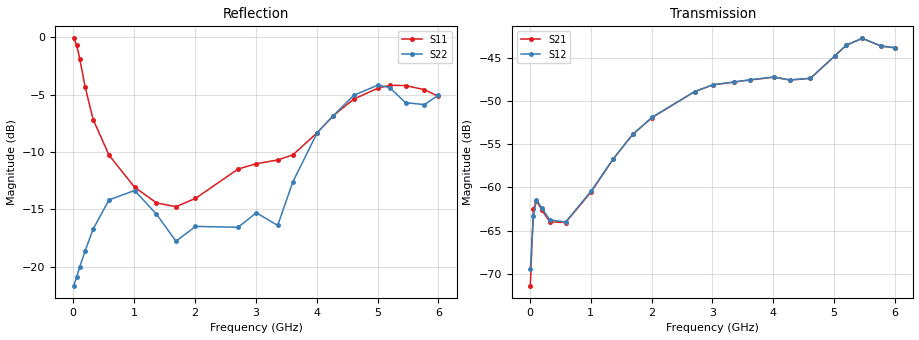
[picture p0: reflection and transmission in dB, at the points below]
!Agilent Technologies,N5230A,MY45001650,A.07.50.48
!Agilent N5230A: A.07.50.48
!Date: Saturday, July 08, 2017 15:49:07
!Correction: S11(Full 2 Port(1,2))
!S21(Full 2 Port(1,2))
!S12(Full 2 Port(1,2))
!S22(Full 2 Port(1,2))
!S2P File: Measurements: S11, S21, S12, S22:
# Hz S  dB  R 50
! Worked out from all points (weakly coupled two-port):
!   600 points, 10 MHz to 6 GHz, reference 50 ohm
!   highest |S21| = -42.73 dB at 5.46 GHz (marker M1); lowest = -71.4 dB at 10 MHz (marker M2)
!   lowest |S11| = -14.8 dB at 1.69 GHz (marker M3), VSWR 1.45, Z = 34.6 + j1.17 ohm
!   |S11| at or under -10 dB: 552.8 MHz to 3.663 GHz (3.11 GHz wide, 148 % of centre)
!   |S22| runs from -21.6 to -4.1 dB; largest |S21 - S12| = 0.00052
!   S11 on the Smith chart (normalised r, x): 10 MHz: 3, -20; 110 MHz: 0.52, -1.89; 330 MHz: 0.55, -0.56; 2.71 GHz: 0.59, +0.09; 4.27 GHz: 1.39, +1.14; 6 GHz: 2.58, -1.43
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1e7  -0.11 -5.7  -71.39 -163.1  -69.43 78.4  -21.65 -6.3
6e7  -0.70 -31.6  -62.51 26.6  -63.35 24.8  -20.89 -20.2
1.1e8  -1.91 -53.1  -61.55 -7.9  -61.43 -8.8  -20.00 -35.1
2e8  -4.38 -81.2  -62.64 -41.7  -62.42 -42.0  -18.59 -57.9
3.3e8  -7.18 -109.0  -63.99 -69.0  -63.77 -69.9  -16.71 -82.8
5.9e8  -10.28 -143.8  -64.07 -114.5  -64.01 -114.3  -14.18 -116.4
1.01e9  -13.07 -172.4  -60.51 -176.9  -60.41 -177.2  -13.36 -153.3
1.37e9  -14.44 174.1  -56.72 141.1  -56.70 141.3  -15.42 174.8
1.69e9  -14.77 174.8  -53.86 107.8  -53.87 107.8  -17.78 168.9
2.01e9  -14.05 177.0  -51.91 77.3  -51.86 77.2  -16.49 159.7
2.71e9  -11.49 164.5  -48.89 20.6  -48.89 20.5  -16.56 137.0
3.01e9  -11.03 149.3  -48.12 -4.4  -48.11 -4.4  -15.30 132.1
3.36e9  -10.70 124.6  -47.79 -31.9  -47.78 -31.9  -16.40 149.6
3.61e9  -10.26 102.1  -47.56 -49.9  -47.53 -49.8  -12.60 168.7
4.01e9  -8.32 64.2  -47.23 -80.3  -47.21 -80.0  -8.32 157.7
4.27e9  -6.86 45.6  -47.55 -99.6  -47.55 -99.6  -6.87 150.4
4.61e9  -5.40 27.7  -47.37 -116.6  -47.35 -116.6  -5.07 133.8
5.01e9  -4.44 13.0  -44.77 -145.6  -44.75 -145.4  -4.17 104.2
5.2e9  -4.20 7.8  -43.52 -167.1  -43.50 -167.0  -4.40 89.8
5.46e9  -4.22 -0.4  -42.73 157.4  -42.73 157.5  -5.71 75.1
5.77e9  -4.58 -10.8  -43.63 119.7  -43.61 119.8  -5.88 69.2
6e9  -5.16 -20.4  -43.84 101.4  -43.80 101.4  -5.05 56.7
